One B-rep face of a CAD part: STEP entity #1275.
In plain terms, the planar face has unit normal (0, 1, 0).
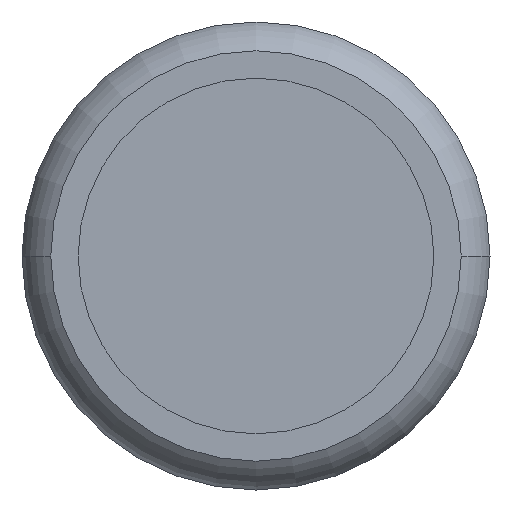
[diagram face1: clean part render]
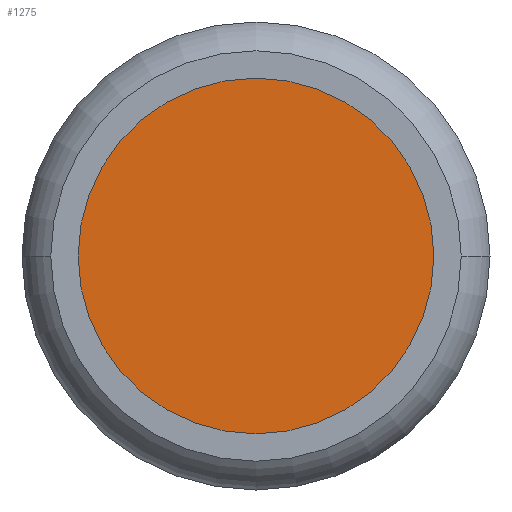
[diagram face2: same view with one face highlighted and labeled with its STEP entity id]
Its self-contained STEP definition (entity closure, numbers rounded to 3 decimals):
#156 = CARTESIAN_POINT ( 'NONE',  ( -2.192, 2.45, 10. ) ) ;
#167 = CARTESIAN_POINT ( 'NONE',  ( 0., 2.45, 1.9 ) ) ;
#1275 = ADVANCED_FACE ( 'NONE', ( #8504 ), #2849, .F. ) ;
#1458 = EDGE_CURVE ( 'NONE', #11984, #6318, #5469, .T. ) ;
#1466 = CARTESIAN_POINT ( 'NONE',  ( 0., 2.45, -1.9 ) ) ;
#1566 = EDGE_CURVE ( 'NONE', #6318, #11984, #6245, .T. ) ;
#1763 = DIRECTION ( 'NONE',  ( 0., -1., 0. ) ) ;
#2367 = DIRECTION ( 'NONE',  ( 0., -1., 0. ) ) ;
#2489 = AXIS2_PLACEMENT_3D ( 'NONE', #156, #1763, #2737 ) ;
#2712 = DIRECTION ( 'NONE',  ( 0., -1., 0. ) ) ;
#2737 = DIRECTION ( 'NONE',  ( 0., 0., -1. ) ) ;
#2750 = ORIENTED_EDGE ( 'NONE', *, *, #1566, .F. ) ;
#2849 = PLANE ( 'NONE',  #2489 ) ;
#2962 = AXIS2_PLACEMENT_3D ( 'NONE', #5442, #2712, #5322 ) ;
#4696 = ORIENTED_EDGE ( 'NONE', *, *, #1458, .F. ) ;
#4900 = AXIS2_PLACEMENT_3D ( 'NONE', #6168, #2367, #7649 ) ;
#5322 = DIRECTION ( 'NONE',  ( 0., 0., -1. ) ) ;
#5442 = CARTESIAN_POINT ( 'NONE',  ( 0., 2.45, 0. ) ) ;
#5469 = CIRCLE ( 'NONE', #4900, 1.9 ) ;
#6168 = CARTESIAN_POINT ( 'NONE',  ( 0., 2.45, 0. ) ) ;
#6245 = CIRCLE ( 'NONE', #2962, 1.9 ) ;
#6318 = VERTEX_POINT ( 'NONE', #167 ) ;
#7649 = DIRECTION ( 'NONE',  ( 0., 0., -1. ) ) ;
#8504 = FACE_OUTER_BOUND ( 'NONE', #11311, .T. ) ;
#11311 = EDGE_LOOP ( 'NONE', ( #2750, #4696 ) ) ;
#11984 = VERTEX_POINT ( 'NONE', #1466 ) ;
